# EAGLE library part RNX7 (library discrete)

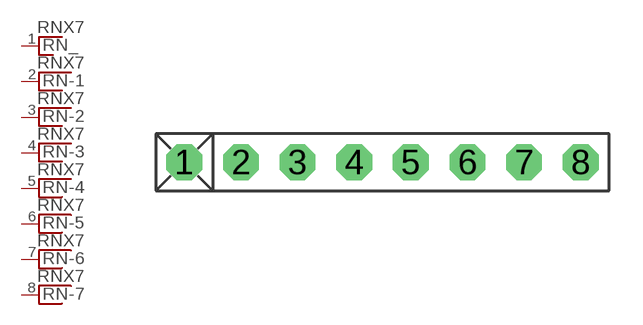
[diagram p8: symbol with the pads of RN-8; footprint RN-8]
Designator prefix RN; gates _=RN_1 -1=RNX -2=RNX -3=RNX -4=RNX -5=RNX -6=RNX -7=RNX

## RNX7  [RN-8]
1  _:1  pas
2  -1:1  pas
3  -2:1  pas
4  -3:1  pas
5  -4:1  pas
6  -5:1  pas
7  -6:1  pas
8  -7:1  pas

## Footprint RN-8 (pad centres in mm)
drill 0.813 pad 1.6 octagon: 1 -8.89,0; 2 -6.35,0; 3 -3.81,0; 4 -1.27,0; 5 1.27,0; 6 3.81,0; 7 6.35,0; 8 8.89,0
